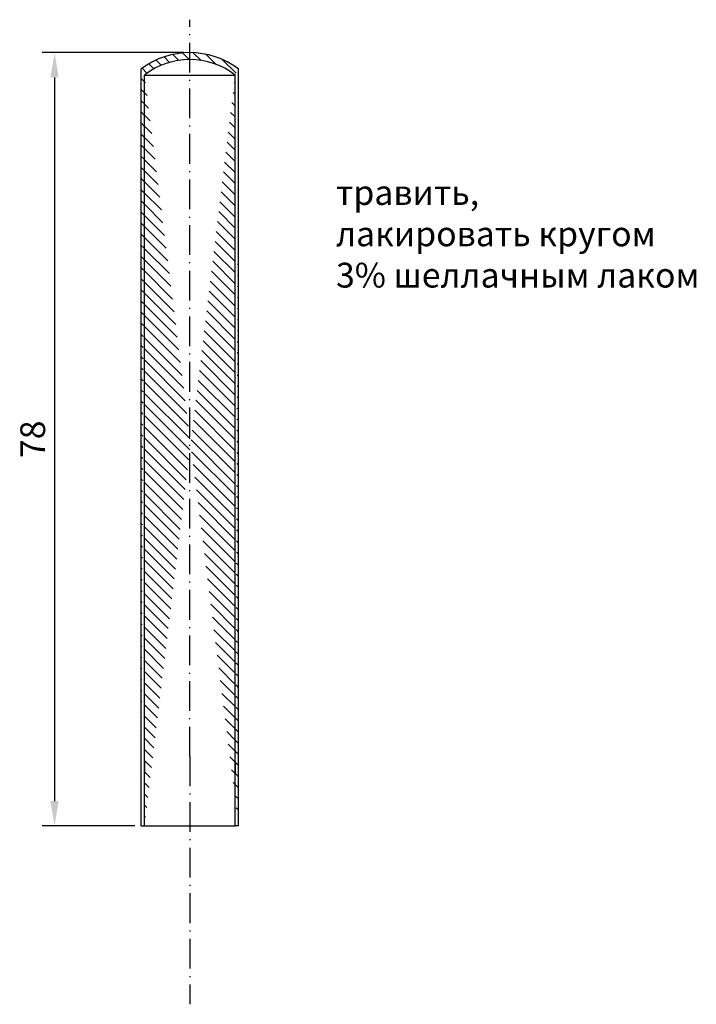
# Model space of a CAD drawing. Units: millimetres. Extents: x -17.2 to 51.1, y -24.5 to 74.8.
import ezdxf

# ---------------------------------------------------------------- set-up
doc = ezdxf.new("R2010")
doc.units = ezdxf.units.MM
doc.linetypes.add('ACAD_ISO10W100', pattern=[18, 12, -3, 0, -3])
doc.dimstyles.new('ISO-25', dxfattribs={"dimtxt": 2.5, "dimasz": 2.5, "dimexe": 1.25, "dimexo": 0.625, "dimtad": 1, "dimtxsty": 'Standard', "dimcen": 2.5, "dimadec": 0, "dimazin": 0, "dimtfac": 1, "dimtmove": 0, "dimatfit": 3, "dimfxl": 0, "dimarcsym": 0})

# ---------------------------------------------------------------- blocks, each defined once
blk = doc.blocks.new('*D5')
at = {"color": 0, "lineweight": -2, "ltscale": 0.25}
for p, q in [((-0.6249999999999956, 71.49999999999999), (-14.90119020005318, 71.49999999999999)), ((-13.65119020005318, 68.99999999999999), (-13.65119020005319, -3.999999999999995)), ((-5.535000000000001, -6.499999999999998), (-14.9011902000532, -6.499999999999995))]:
    blk.add_line(p, q, dxfattribs=at)
at = {"color": 0, "lineweight": 15, "ltscale": 0.25}
for points in [[(-14.06785686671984, 68.99999999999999), (-13.23452353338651, 68.99999999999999), (-13.65119020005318, 71.49999999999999)], [(-14.06785686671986, -3.999999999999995), (-13.23452353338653, -3.999999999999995), (-13.65119020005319, -6.499999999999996)]]:
    blk.add_solid(points, dxfattribs=at)
at = {"layer": 'Defpoints', "color": 0, "lineweight": 15, "ltscale": 0.25}
for p in [(4.469813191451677e-15, 71.49999999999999), (-13.65119020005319, -6.499999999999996), (-4.910000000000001, -6.499999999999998)]:
    blk.add_point(p, dxfattribs=at)
at = {"color": 0, "lineweight": 15, "ltscale": 0.25, "insert": (-15.52619020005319, 32.49999999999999), "char_height": 2.5, "attachment_point": 5, "rotation": 90}
blk.add_mtext('78', dxfattribs=at)

msp = doc.modelspace()

# ---------------------------------------------------------------- hatches: boundary and pattern name
at = {"lineweight": 15, "ltscale": 0.25}
h = msp.add_hatch(dxfattribs=at)
h.set_pattern_fill('ANSI31', scale=0.25, angle=90, style=0)
h.set_pattern_definition([(135, (0, 0), (-0.5612660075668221, -0.561266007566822), [])])
edge = h.paths.add_edge_path()
edge.add_line((-4.574999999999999, -6.499999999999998), (-4.574999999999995, 69.24301060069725))
edge.add_line((-4.910000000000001, -6.499999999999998), (-4.909999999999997, 69.8674881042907))
edge.add_arc((3.385697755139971e-15, 63.29999999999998), 8.200000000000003, 53.21739364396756, 126.7826063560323)
edge.add_arc((3.385697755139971e-15, 63.29999999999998), 7.5, 52.41049703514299, 127.5895029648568)
edge.add_line((4.909999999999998, -6.5), (4.910000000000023, 69.86748810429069))
edge.add_line((4.574999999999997, -6.5), (4.575000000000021, 69.24301060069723))

# ---------------------------------------------------------------- linework, layer by layer
at = {"color": 1, "linetype": 'ACAD_ISO10W100', "lineweight": 25, "ltscale": 0.25}
for q in [(4.673465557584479e-15, 74.82600538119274), (-4.469813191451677e-15, -24.5)]:
    msp.add_line((1.224606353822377e-16, 0.5), q, dxfattribs=at)
at = {"color": 7, "linetype": 'ByBlock', "lineweight": 30}
for p, q in [((-4.910000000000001, -6.499999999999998), (-4.909999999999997, 69.8674881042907)), ((4.909999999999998, -6.5), (4.910000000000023, 69.86748810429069)), ((-4.574999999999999, -6.499999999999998), (-4.574999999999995, 69.24301060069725)), ((4.574999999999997, -6.5), (4.575000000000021, 69.24301060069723)), ((-4.575, 0), (-4.575, -1.2)), ((4.575, -1.680772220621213e-15), (4.575, -1.200000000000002)), ((-4.574999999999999, -6.499999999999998), (-4.574999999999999, -4.699999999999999)), ((4.574999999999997, -6.500000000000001), (4.574999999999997, -4.700000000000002)), ((-4.910000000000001, -6.499999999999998), (-4.574999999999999, -6.499999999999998)), ((4.909999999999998, -6.500000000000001), (4.574999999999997, -6.500000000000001))]:
    msp.add_line(p, q, dxfattribs=at)
at = {"color": 7, "lineweight": 30, "ltscale": 0.25}
for p, q in [((-4.574999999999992, 69.24301060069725), (4.574999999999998, 69.24301060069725)), ((-4.574999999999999, -6.499999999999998), (4.574999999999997, -6.500000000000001))]:
    msp.add_line(p, q, dxfattribs=at)
at = {"color": 7, "lineweight": 15, "ltscale": 0.25}
for p, q in [((-4.910000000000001, -6.499999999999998), (-4.574999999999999, -6.499999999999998)), ((4.574999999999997, -6.500000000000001), (4.909999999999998, -6.5))]:
    msp.add_line(p, q, dxfattribs=at)
at = {"color": 7, "linetype": 'ByBlock', "lineweight": 30}
for radius, start, end in [(8.200000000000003, 53.21739364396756, 126.7826063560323), (7.5, 52.41049703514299, 127.5895029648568)]:
    msp.add_arc((3.385697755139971e-15, 63.29999999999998), radius, start, end, dxfattribs=at)

# ---------------------------------------------------------------- texts
at = {"color": 7, "lineweight": 15, "ltscale": 0.25}
for s, p in [('травить, ', (14.75068044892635, 56.1379282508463)), ('лакировать кругом', (14.75068044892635, 51.97126158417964)), ('3% шеллачным лаком', (14.75068044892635, 47.80459491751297))]:
    msp.add_text(s, height=2.5, dxfattribs=at).set_placement(p)

# ---------------------------------------------------------------- dimensions: what is measured, and where the dimension line sits
at = {"color": 3, "lineweight": 15, "ltscale": 0.25}
dim = msp.add_linear_dim(base=(-13.65119020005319, -6.499999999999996), p1=(4.469813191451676e-15, 71.49999999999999), p2=(-4.910000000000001, -6.499999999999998), angle=90, dimstyle='ISO-25', dxfattribs=at)
dim.commit()
dim.dimension.update_dxf_attribs({"geometry": '*D5', "text_midpoint": (-15.52619020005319, 32.49999999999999)})

doc.saveas('drawing.dxf')
